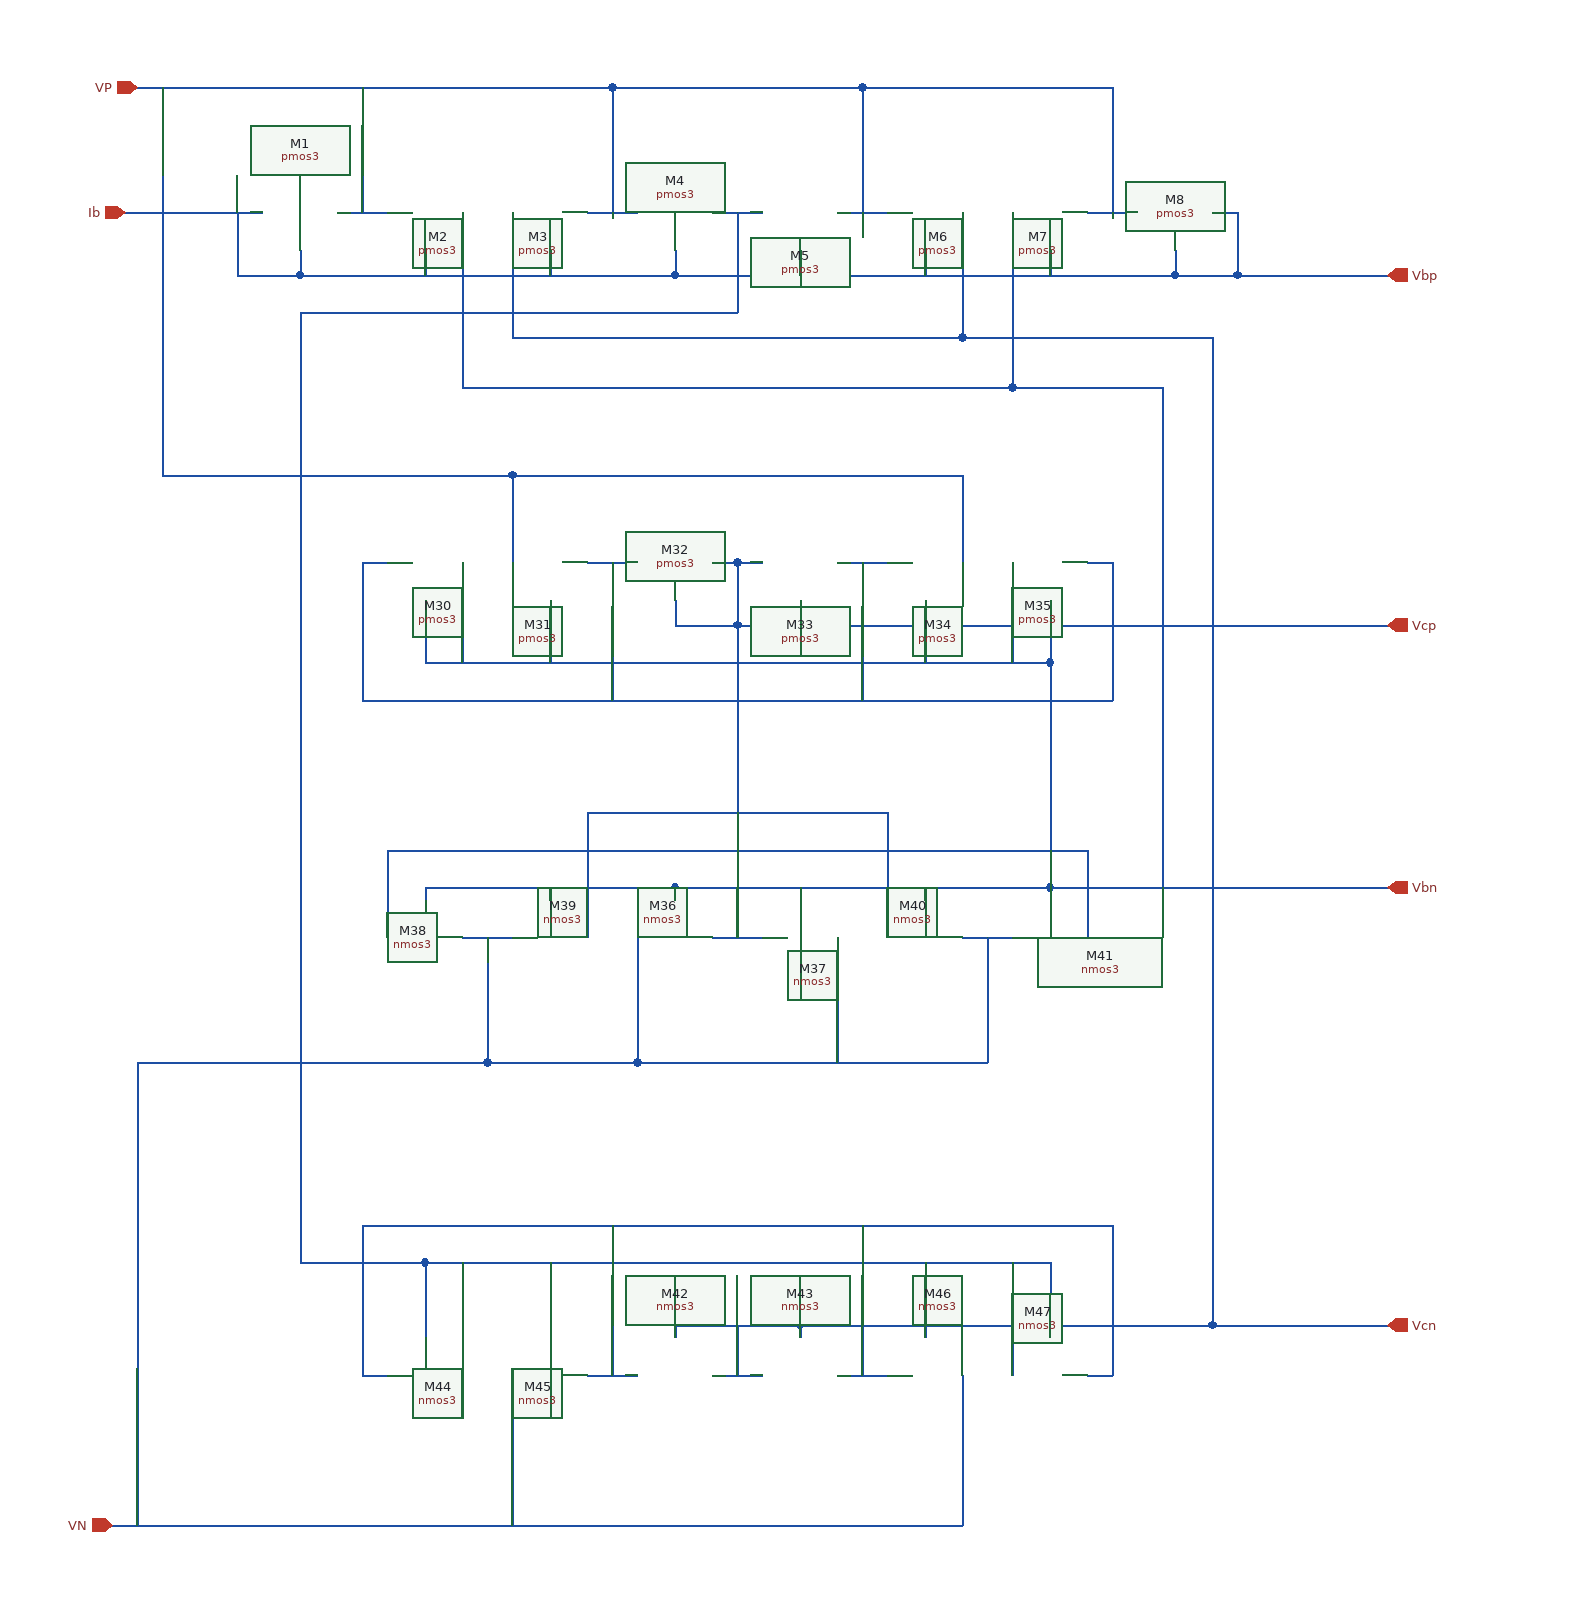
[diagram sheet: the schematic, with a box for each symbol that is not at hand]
v {xschem version=2.9.9 file_version=1.2 }
G {}
K {}
V {}
S {}
E {}
N 240 -1090 280 -1090 { lab=Ib}
N 310 -1040 610 -1040 { lab=Ib}
N 610 -1060 610 -1040 { lab=Ib}
N 510 -1060 510 -1040 { lab=Ib}
N 410 -1060 410 -1040 { lab=Ib}
N 310 -1060 310 -1040 { lab=Ib}
N 260 -1090 260 -1040 { lab=Ib}
N 260 -1040 310 -1040 { lab=Ib}
N 340 -1090 380 -1090 { lab=VP}
N 540 -1090 580 -1090 { lab=VP}
N 560 -1190 560 -1090 { lab=VP}
N 360 -1190 360 -1090 { lab=VP}
N 180 -1190 560 -1190 { lab=VP}
N 610 -1040 1010 -1040 { lab=Ib}
N 1010 -1060 1010 -1040 { lab=Ib}
N 910 -1060 910 -1040 { lab=Ib}
N 810 -1060 810 -1040 { lab=Ib}
N 710 -1060 710 -1040 { lab=Ib}
N 740 -1090 780 -1090 { lab=VP}
N 940 -1090 980 -1090 { lab=VP}
N 760 -1190 760 -1090 { lab=VP}
N 560 -1190 760 -1190 { lab=VP}
N 960 -1190 960 -1090 { lab=VP}
N 760 -1190 960 -1190 { lab=VP}
N 640 -1090 680 -1090 { lab=#net1}
N 1010 -1040 1060 -1040 { lab=Ib}
N 1060 -1090 1060 -1040 { lab=Ib}
N 440 -1090 440 -950 { lab=#net2}
N 440 -950 880 -950 { lab=#net2}
N 880 -1090 880 -950 { lab=#net2}
N 480 -1090 480 -990 { lab=Vcn}
N 480 -990 840 -990 { lab=Vcn}
N 840 -1090 840 -990 { lab=Vcn}
N 1040 -1090 1060 -1090 { lab=Ib}
N 610 -780 610 -760 { lab=Vcp}
N 610 -760 660 -760 { lab=Vcp}
N 660 -810 660 -760 { lab=Vcp}
N 640 -810 660 -810 { lab=Vcp}
N 360 -810 380 -810 { lab=#net3}
N 540 -810 580 -810 { lab=#net3}
N 480 -880 480 -810 { lab=VP}
N 280 -880 480 -880 { lab=VP}
N 660 -810 680 -810 { lab=Vcp}
N 660 -760 710 -760 { lab=Vcp}
N 710 -780 710 -760 { lab=Vcp}
N 480 -880 840 -880 { lab=VP}
N 840 -880 840 -810 { lab=VP}
N 740 -810 780 -810 { lab=#net3}
N 940 -810 960 -810 { lab=#net3}
N 960 -810 960 -700 { lab=#net3}
N 360 -810 360 -700 { lab=#net3}
N 360 -700 960 -700 { lab=#net3}
N 560 -810 560 -700 { lab=#net3}
N 760 -810 760 -700 { lab=#net3}
N 410 -780 410 -730 { lab=#net4}
N 510 -780 510 -730 { lab=#net4}
N 810 -780 810 -730 { lab=#net4}
N 910 -780 910 -730 { lab=#net4}
N 410 -730 910 -730 { lab=#net4}
N 440 -510 480 -510 { lab=VN}
N 460 -510 460 -410 { lab=VN}
N 280 -410 460 -410 { lab=VN}
N 580 -510 580 -410 { lab=VN}
N 460 -410 580 -410 { lab=VN}
N 610 -550 610 -540 { lab=#net2}
N 410 -550 610 -550 { lab=#net2}
N 410 -550 410 -540 { lab=#net2}
N 510 -550 510 -540 { lab=#net2}
N 540 -610 540 -510 { lab=Vcp}
N 380 -580 380 -510 { lab=#net4}
N 660 -550 660 -510 { lab=#net2}
N 610 -550 910 -550 { lab=#net2}
N 910 -550 910 -540 { lab=#net2}
N 810 -550 810 -540 { lab=#net2}
N 710 -550 710 -540 { lab=#net2}
N 640 -510 680 -510 { lab=#net2}
N 840 -510 880 -510 { lab=VN}
N 860 -510 860 -410 { lab=VN}
N 580 -410 860 -410 { lab=VN}
N 740 -510 740 -410 { lab=VN}
N 780 -610 780 -510 { lab=Vcp}
N 540 -610 780 -610 { lab=Vcp}
N 380 -580 940 -580 { lab=#net4}
N 940 -580 940 -510 { lab=#net4}
N 840 -160 840 -40 { lab=VN}
N 480 -160 480 -40 { lab=VN}
N 280 -40 840 -40 { lab=VN}
N 640 -160 680 -160 { lab=Vcn}
N 610 -200 610 -190 { lab=Vcn}
N 610 -200 710 -200 { lab=Vcn}
N 710 -200 710 -190 { lab=Vcn}
N 660 -200 660 -160 { lab=Vcn}
N 540 -160 580 -160 { lab=#net5}
N 740 -160 780 -160 { lab=#net5}
N 360 -160 380 -160 { lab=#net5}
N 360 -280 360 -160 { lab=#net5}
N 360 -280 960 -280 { lab=#net5}
N 960 -280 960 -160 { lab=#net5}
N 940 -160 960 -160 { lab=#net5}
N 410 -250 410 -190 { lab=#net1}
N 410 -250 910 -250 { lab=#net1}
N 910 -250 910 -190 { lab=#net1}
N 810 -250 810 -190 { lab=#net1}
N 510 -250 510 -190 { lab=#net1}
N 710 -200 1040 -200 { lab=Vcn}
N 160 -40 280 -40 { lab=VN}
N 1040 -200 1180 -200 { lab=Vcn}
N 880 -950 1000 -950 { lab=#net2}
N 1000 -950 1000 -550 { lab=#net2}
N 840 -990 1040 -990 { lab=Vcn}
N 1040 -990 1040 -200 { lab=Vcn}
N 710 -760 1180 -760 { lab=Vcp}
N 910 -550 1180 -550 { lab=#net2}
N 660 -760 660 -610 { lab=Vcp}
N 660 -1090 660 -1010 { lab=#net1}
N 310 -1010 660 -1010 { lab=#net1}
N 310 -1010 310 -280 { lab=#net1}
N 310 -250 410 -250 { lab=#net1}
N 310 -280 310 -250 { lab=#net1}
N 910 -730 910 -580 { lab=#net4}
N 880 -810 880 -730 { lab=#net4}
N 440 -810 440 -730 { lab=#net4}
N 880 -250 880 -160 { lab=#net1}
N 440 -250 440 -160 { lab=#net1}
N 760 -280 760 -160 { lab=#net5}
N 560 -280 560 -160 { lab=#net5}
N 1060 -1040 1180 -1040 { lab=Vbp}
N 180 -410 180 -40 { lab=VN}
N 180 -410 280 -410 { lab=VN}
N 170 -1090 240 -1090 { lab=Ib}
N 200 -1190 200 -880 { lab=VP}
N 200 -880 280 -880 { lab=VP}
C {madvlsi/pmos3.sym} 310 -1090 3 0 {name=M1
L=0.5
W=12
body=VDD
nf=1
mult=1
ad="'int((nf+1)/2) * W/nf * 0.29'" 
pd="'2*int((nf+1)/2) * (W/nf + 0.29)'"
as="'int((nf+2)/2) * W/nf * 0.29'" 
ps="'2*int((nf+2)/2) * (W/nf + 0.29)'"
nrd="'0.29 / W'" nrs="'0.29 / W'"
sa=0 sb=0 sd=0
model=pfet_01v8
spiceprefix=X
}
C {madvlsi/pmos3.sym} 410 -1090 3 0 {name=M2
L=0.5
W=12
body=VDD
nf=1
mult=1
ad="'int((nf+1)/2) * W/nf * 0.29'" 
pd="'2*int((nf+1)/2) * (W/nf + 0.29)'"
as="'int((nf+2)/2) * W/nf * 0.29'" 
ps="'2*int((nf+2)/2) * (W/nf + 0.29)'"
nrd="'0.29 / W'" nrs="'0.29 / W'"
sa=0 sb=0 sd=0
model=pfet_01v8
spiceprefix=X
}
C {madvlsi/pmos3.sym} 510 -1090 3 0 {name=M3
L=0.5
W=12
body=VDD
nf=1
mult=1
ad="'int((nf+1)/2) * W/nf * 0.29'" 
pd="'2*int((nf+1)/2) * (W/nf + 0.29)'"
as="'int((nf+2)/2) * W/nf * 0.29'" 
ps="'2*int((nf+2)/2) * (W/nf + 0.29)'"
nrd="'0.29 / W'" nrs="'0.29 / W'"
sa=0 sb=0 sd=0
model=pfet_01v8
spiceprefix=X
}
C {madvlsi/pmos3.sym} 610 -1090 3 0 {name=M4
L=0.5
W=12
body=VDD
nf=1
mult=1
ad="'int((nf+1)/2) * W/nf * 0.29'" 
pd="'2*int((nf+1)/2) * (W/nf + 0.29)'"
as="'int((nf+2)/2) * W/nf * 0.29'" 
ps="'2*int((nf+2)/2) * (W/nf + 0.29)'"
nrd="'0.29 / W'" nrs="'0.29 / W'"
sa=0 sb=0 sd=0
model=pfet_01v8
spiceprefix=X
}
C {madvlsi/pmos3.sym} 710 -1090 3 0 {name=M5
L=0.5
W=12
body=VDD
nf=1
mult=1
ad="'int((nf+1)/2) * W/nf * 0.29'" 
pd="'2*int((nf+1)/2) * (W/nf + 0.29)'"
as="'int((nf+2)/2) * W/nf * 0.29'" 
ps="'2*int((nf+2)/2) * (W/nf + 0.29)'"
nrd="'0.29 / W'" nrs="'0.29 / W'"
sa=0 sb=0 sd=0
model=pfet_01v8
spiceprefix=X
}
C {madvlsi/pmos3.sym} 810 -1090 3 0 {name=M6
L=0.5
W=12
body=VDD
nf=1
mult=1
ad="'int((nf+1)/2) * W/nf * 0.29'" 
pd="'2*int((nf+1)/2) * (W/nf + 0.29)'"
as="'int((nf+2)/2) * W/nf * 0.29'" 
ps="'2*int((nf+2)/2) * (W/nf + 0.29)'"
nrd="'0.29 / W'" nrs="'0.29 / W'"
sa=0 sb=0 sd=0
model=pfet_01v8
spiceprefix=X
}
C {madvlsi/pmos3.sym} 910 -1090 3 0 {name=M7
L=0.5
W=12
body=VDD
nf=1
mult=1
ad="'int((nf+1)/2) * W/nf * 0.29'" 
pd="'2*int((nf+1)/2) * (W/nf + 0.29)'"
as="'int((nf+2)/2) * W/nf * 0.29'" 
ps="'2*int((nf+2)/2) * (W/nf + 0.29)'"
nrd="'0.29 / W'" nrs="'0.29 / W'"
sa=0 sb=0 sd=0
model=pfet_01v8
spiceprefix=X
}
C {madvlsi/pmos3.sym} 1010 -1090 3 0 {name=M8
L=0.5
W=12
body=VDD
nf=1
mult=1
ad="'int((nf+1)/2) * W/nf * 0.29'" 
pd="'2*int((nf+1)/2) * (W/nf + 0.29)'"
as="'int((nf+2)/2) * W/nf * 0.29'" 
ps="'2*int((nf+2)/2) * (W/nf + 0.29)'"
nrd="'0.29 / W'" nrs="'0.29 / W'"
sa=0 sb=0 sd=0
model=pfet_01v8
spiceprefix=X
}
C {madvlsi/pmos3.sym} 410 -810 3 0 {name=M30
L=0.5
W=12
body=VDD
nf=1
mult=1
ad="'int((nf+1)/2) * W/nf * 0.29'" 
pd="'2*int((nf+1)/2) * (W/nf + 0.29)'"
as="'int((nf+2)/2) * W/nf * 0.29'" 
ps="'2*int((nf+2)/2) * (W/nf + 0.29)'"
nrd="'0.29 / W'" nrs="'0.29 / W'"
sa=0 sb=0 sd=0
model=pfet_01v8
spiceprefix=X
}
C {madvlsi/pmos3.sym} 510 -810 3 0 {name=M31
L=0.5
W=12
body=VDD
nf=1
mult=1
ad="'int((nf+1)/2) * W/nf * 0.29'" 
pd="'2*int((nf+1)/2) * (W/nf + 0.29)'"
as="'int((nf+2)/2) * W/nf * 0.29'" 
ps="'2*int((nf+2)/2) * (W/nf + 0.29)'"
nrd="'0.29 / W'" nrs="'0.29 / W'"
sa=0 sb=0 sd=0
model=pfet_01v8
spiceprefix=X
}
C {madvlsi/pmos3.sym} 610 -810 3 0 {name=M32
L=0.5
W=12
body=VDD
nf=1
mult=1
ad="'int((nf+1)/2) * W/nf * 0.29'" 
pd="'2*int((nf+1)/2) * (W/nf + 0.29)'"
as="'int((nf+2)/2) * W/nf * 0.29'" 
ps="'2*int((nf+2)/2) * (W/nf + 0.29)'"
nrd="'0.29 / W'" nrs="'0.29 / W'"
sa=0 sb=0 sd=0
model=pfet_01v8
spiceprefix=X
}
C {madvlsi/pmos3.sym} 710 -810 3 0 {name=M33
L=0.5
W=12
body=VDD
nf=1
mult=1
ad="'int((nf+1)/2) * W/nf * 0.29'" 
pd="'2*int((nf+1)/2) * (W/nf + 0.29)'"
as="'int((nf+2)/2) * W/nf * 0.29'" 
ps="'2*int((nf+2)/2) * (W/nf + 0.29)'"
nrd="'0.29 / W'" nrs="'0.29 / W'"
sa=0 sb=0 sd=0
model=pfet_01v8
spiceprefix=X
}
C {madvlsi/pmos3.sym} 810 -810 3 0 {name=M34
L=0.5
W=12
body=VDD
nf=1
mult=1
ad="'int((nf+1)/2) * W/nf * 0.29'" 
pd="'2*int((nf+1)/2) * (W/nf + 0.29)'"
as="'int((nf+2)/2) * W/nf * 0.29'" 
ps="'2*int((nf+2)/2) * (W/nf + 0.29)'"
nrd="'0.29 / W'" nrs="'0.29 / W'"
sa=0 sb=0 sd=0
model=pfet_01v8
spiceprefix=X
}
C {madvlsi/pmos3.sym} 910 -810 3 0 {name=M35
L=0.5
W=12
body=VDD
nf=1
mult=1
ad="'int((nf+1)/2) * W/nf * 0.29'" 
pd="'2*int((nf+1)/2) * (W/nf + 0.29)'"
as="'int((nf+2)/2) * W/nf * 0.29'" 
ps="'2*int((nf+2)/2) * (W/nf + 0.29)'"
nrd="'0.29 / W'" nrs="'0.29 / W'"
sa=0 sb=0 sd=0
model=pfet_01v8
spiceprefix=X
}
C {madvlsi/nmos3.sym} 610 -510 1 0 {name=M36
L=0.5
W=12
body=GND
nf=1
mult=1
ad="'int((nf+1)/2) * W/nf * 0.29'" 
pd="'2*int((nf+1)/2) * (W/nf + 0.29)'"
as="'int((nf+2)/2) * W/nf * 0.29'" 
ps="'2*int((nf+2)/2) * (W/nf + 0.29)'"
nrd="'0.29 / W'" nrs="'0.29 / W'"
sa=0 sb=0 sd=0
model=nfet_01v8
spiceprefix=X
}
C {madvlsi/nmos3.sym} 710 -510 1 0 {name=M37
L=0.5
W=12
body=GND
nf=1
mult=1
ad="'int((nf+1)/2) * W/nf * 0.29'" 
pd="'2*int((nf+1)/2) * (W/nf + 0.29)'"
as="'int((nf+2)/2) * W/nf * 0.29'" 
ps="'2*int((nf+2)/2) * (W/nf + 0.29)'"
nrd="'0.29 / W'" nrs="'0.29 / W'"
sa=0 sb=0 sd=0
model=nfet_01v8
spiceprefix=X
}
C {madvlsi/nmos3.sym} 410 -510 1 0 {name=M38
L=0.5
W=12
body=GND
nf=1
mult=1
ad="'int((nf+1)/2) * W/nf * 0.29'" 
pd="'2*int((nf+1)/2) * (W/nf + 0.29)'"
as="'int((nf+2)/2) * W/nf * 0.29'" 
ps="'2*int((nf+2)/2) * (W/nf + 0.29)'"
nrd="'0.29 / W'" nrs="'0.29 / W'"
sa=0 sb=0 sd=0
model=nfet_01v8
spiceprefix=X
}
C {madvlsi/nmos3.sym} 510 -510 1 0 {name=M39
L=0.5
W=12
body=GND
nf=1
mult=1
ad="'int((nf+1)/2) * W/nf * 0.29'" 
pd="'2*int((nf+1)/2) * (W/nf + 0.29)'"
as="'int((nf+2)/2) * W/nf * 0.29'" 
ps="'2*int((nf+2)/2) * (W/nf + 0.29)'"
nrd="'0.29 / W'" nrs="'0.29 / W'"
sa=0 sb=0 sd=0
model=nfet_01v8
spiceprefix=X
}
C {madvlsi/nmos3.sym} 810 -510 1 0 {name=M40
L=0.5
W=12
body=GND
nf=1
mult=1
ad="'int((nf+1)/2) * W/nf * 0.29'" 
pd="'2*int((nf+1)/2) * (W/nf + 0.29)'"
as="'int((nf+2)/2) * W/nf * 0.29'" 
ps="'2*int((nf+2)/2) * (W/nf + 0.29)'"
nrd="'0.29 / W'" nrs="'0.29 / W'"
sa=0 sb=0 sd=0
model=nfet_01v8
spiceprefix=X
}
C {madvlsi/nmos3.sym} 910 -510 1 0 {name=M41
L=0.5
W=12
body=GND
nf=1
mult=1
ad="'int((nf+1)/2) * W/nf * 0.29'" 
pd="'2*int((nf+1)/2) * (W/nf + 0.29)'"
as="'int((nf+2)/2) * W/nf * 0.29'" 
ps="'2*int((nf+2)/2) * (W/nf + 0.29)'"
nrd="'0.29 / W'" nrs="'0.29 / W'"
sa=0 sb=0 sd=0
model=nfet_01v8
spiceprefix=X
}
C {madvlsi/nmos3.sym} 610 -160 1 0 {name=M42
L=0.5
W=12
body=GND
nf=1
mult=1
ad="'int((nf+1)/2) * W/nf * 0.29'" 
pd="'2*int((nf+1)/2) * (W/nf + 0.29)'"
as="'int((nf+2)/2) * W/nf * 0.29'" 
ps="'2*int((nf+2)/2) * (W/nf + 0.29)'"
nrd="'0.29 / W'" nrs="'0.29 / W'"
sa=0 sb=0 sd=0
model=nfet_01v8
spiceprefix=X
}
C {madvlsi/nmos3.sym} 710 -160 1 0 {name=M43
L=0.5
W=12
body=GND
nf=1
mult=1
ad="'int((nf+1)/2) * W/nf * 0.29'" 
pd="'2*int((nf+1)/2) * (W/nf + 0.29)'"
as="'int((nf+2)/2) * W/nf * 0.29'" 
ps="'2*int((nf+2)/2) * (W/nf + 0.29)'"
nrd="'0.29 / W'" nrs="'0.29 / W'"
sa=0 sb=0 sd=0
model=nfet_01v8
spiceprefix=X
}
C {madvlsi/nmos3.sym} 410 -160 1 0 {name=M44
L=0.5
W=12
body=GND
nf=1
mult=1
ad="'int((nf+1)/2) * W/nf * 0.29'" 
pd="'2*int((nf+1)/2) * (W/nf + 0.29)'"
as="'int((nf+2)/2) * W/nf * 0.29'" 
ps="'2*int((nf+2)/2) * (W/nf + 0.29)'"
nrd="'0.29 / W'" nrs="'0.29 / W'"
sa=0 sb=0 sd=0
model=nfet_01v8
spiceprefix=X
}
C {madvlsi/nmos3.sym} 510 -160 1 0 {name=M45
L=0.5
W=12
body=GND
nf=1
mult=1
ad="'int((nf+1)/2) * W/nf * 0.29'" 
pd="'2*int((nf+1)/2) * (W/nf + 0.29)'"
as="'int((nf+2)/2) * W/nf * 0.29'" 
ps="'2*int((nf+2)/2) * (W/nf + 0.29)'"
nrd="'0.29 / W'" nrs="'0.29 / W'"
sa=0 sb=0 sd=0
model=nfet_01v8
spiceprefix=X
}
C {madvlsi/nmos3.sym} 810 -160 1 0 {name=M46
L=0.5
W=12
body=GND
nf=1
mult=1
ad="'int((nf+1)/2) * W/nf * 0.29'" 
pd="'2*int((nf+1)/2) * (W/nf + 0.29)'"
as="'int((nf+2)/2) * W/nf * 0.29'" 
ps="'2*int((nf+2)/2) * (W/nf + 0.29)'"
nrd="'0.29 / W'" nrs="'0.29 / W'"
sa=0 sb=0 sd=0
model=nfet_01v8
spiceprefix=X
}
C {madvlsi/nmos3.sym} 910 -160 1 0 {name=M47
L=0.5
W=12
body=GND
nf=1
mult=1
ad="'int((nf+1)/2) * W/nf * 0.29'" 
pd="'2*int((nf+1)/2) * (W/nf + 0.29)'"
as="'int((nf+2)/2) * W/nf * 0.29'" 
ps="'2*int((nf+2)/2) * (W/nf + 0.29)'"
nrd="'0.29 / W'" nrs="'0.29 / W'"
sa=0 sb=0 sd=0
model=nfet_01v8
spiceprefix=X
}
C {devices/iopin.sym} 180 -1190 2 0 {name=p1 lab=VP}
C {devices/iopin.sym} 160 -40 2 0 {name=p3 lab=VN}
C {devices/iopin.sym} 170 -1090 2 0 {name=p4 lab=Ib}
C {devices/opin.sym} 1180 -1040 0 0 {name=p2 lab=Vbp}
C {devices/opin.sym} 1180 -760 0 0 {name=p5 lab=Vcp}
C {devices/opin.sym} 1180 -550 0 0 {name=p6 lab=Vbn}
C {devices/opin.sym} 1180 -200 0 0 {name=p7 lab=Vcn
}
